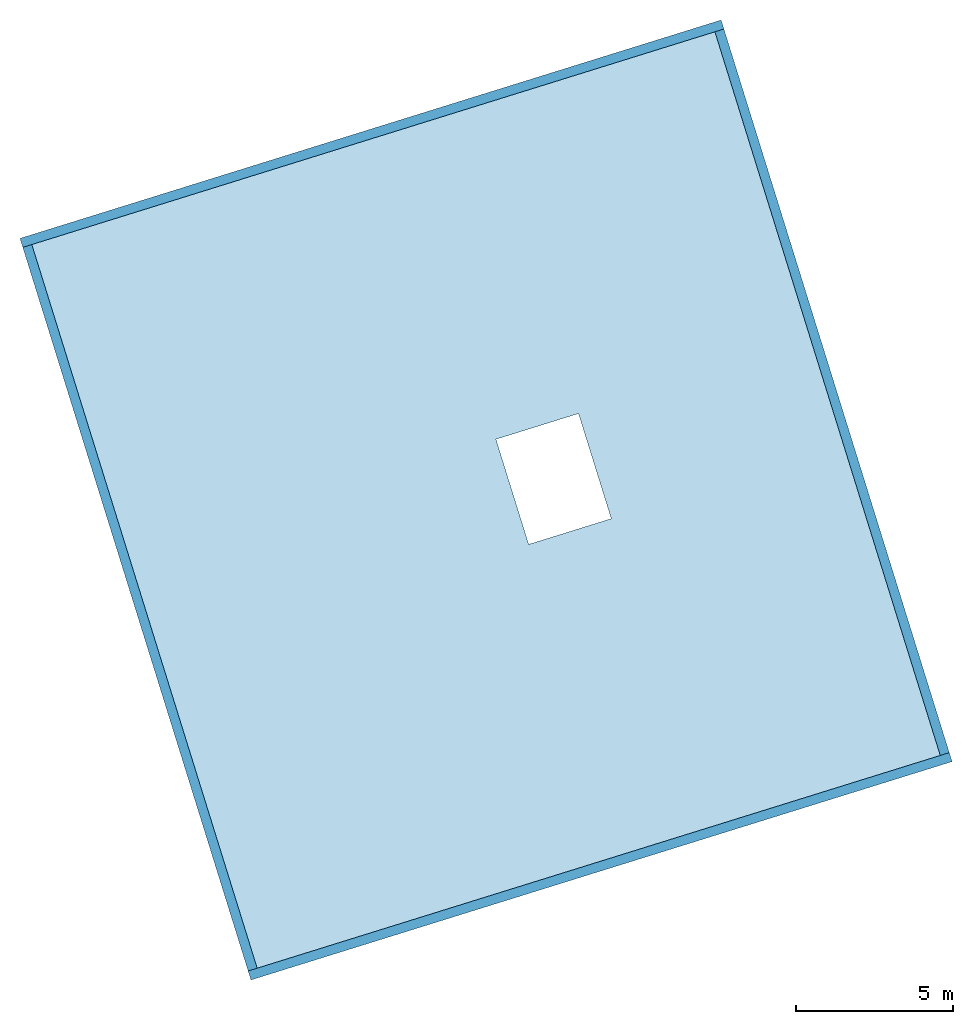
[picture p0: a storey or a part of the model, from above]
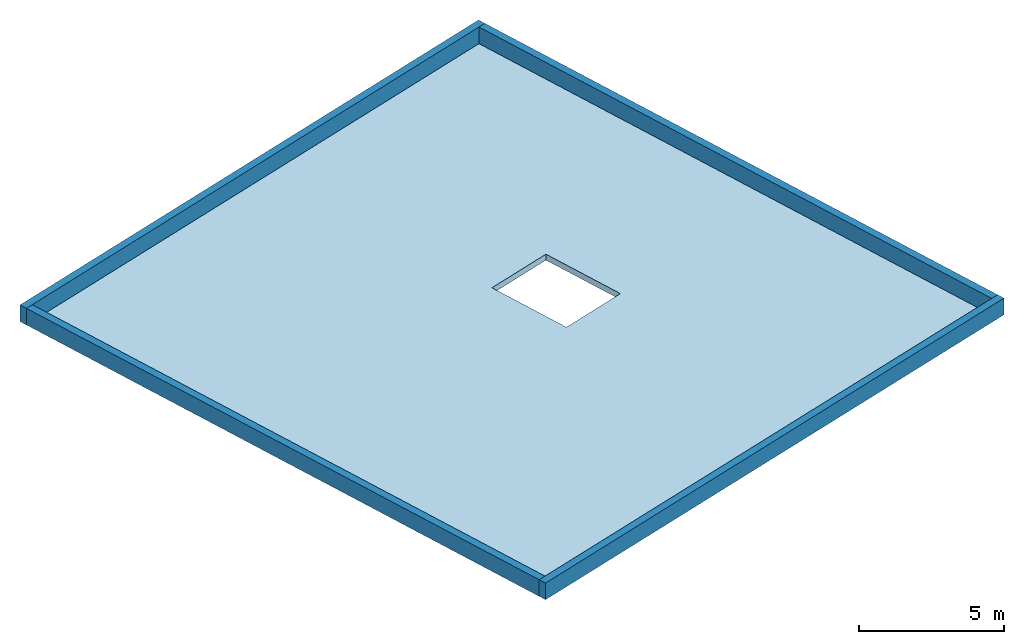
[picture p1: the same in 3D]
Properties of the parts of a building model (IFC4)

# File
Description: ViewDefinition [ReferenceView_V1.2], RevitIdentifiers [ContentGUID: 7b0fba1c-e461-43e6-a004-74300536da52, VersionGUID: d83a99a4-e321-4da3-b3c9-0b0068a0408a, NumberOfSaves: 137], Options [Excluded Entities: IfcGroup;], CoordinateReference [CoordinateBase: Survey Point, ProjectSite: Internal]
File name: MiniBIM 3.1 SO_02_VORM.ifc
Time: 2025-11-03T19:44:00+01:00
Organization: VORM Holding B.V.
Written by: IfcOpenShell 0.8.2
Made in: Bonsai 0.8.2

# IfcProject, 0000
LongName: Voorbeelmodel MiniBIM 3.1 SO-fase; Phase: PROJECTFASE

# IfcSite, Schiehaven
RefLatitude: 51, 54, 13, 78253; RefLongitude: 4, 27, 15, 99642; RefElevation: 3.5 m
Pset_SiteCommon - Reference: Project Information

# IfcBuilding, VORM huis
LongName: VORM huis
Pset_BuildingCommon - Reference: Project Information; NumberOfStoreys: 11; IsLandmarked: no
Pset_BuildingElementProxyCommon - Reference: Project Information; IsExternal: no
Pset_BuildingStoreyCommon - Reference: Project Information; AboveGround: no
Pset_BuildingSystemCommon - Reference: Project Information

# IfcBuildingStorey: Level:Level bouwniveau (PBP) (11)
In: VORM huis
Pset_BuildingStoreyCommon - Reference: Level bouwniveau (PBP)
Name | LongName | Elevation (m) | EntranceLevel | AboveGround
-1 kelder | -1 kelder | -3.2 | no | no
00 begane grond | begane grond | 0 | yes | yes
01 eerste verdieping | 01 eerste verdieping | 3.9 | no | yes
02 tweede verdieping | 02 tweede verdieping | 6.9 | no | yes
03 derde verdieping | 03 derde verdieping | 9.9 | no | yes
04 vierde verdieping | 04 vierde verdieping | 12.9 | no | yes
05 vijfde verdieping | 05 vijfde verdieping | 15.9 | no | yes
06 zesde verdieping | 06 zesde verdieping | 18.9 | no | yes
07 zevende verdieping | 07 zevende verdieping | 21.9 | no | yes
08 achtste verdieping | 08 achtste verdieping | 24.9 | no | yes
09 negende verdieping | 09 negende verdieping | 27.9 | no | yes

# IfcBuildingElementProxy: VORM_coordinatiepunt:CRS-coordinatiepunt, CRS-coordinatiepunt
In: 00 begane grond
Type - Classification: 00.00 (NL-SfB); Material: Blauw, Wit
Pset_BuildingElementProxyCommon - IsExternal: no; Reference: CRS-coordinatiepunt
Pset_EnvironmentalImpactIndicators - Reference: CRS-coordinatiepunt
Qto_BuildingElementProxyQuantities - NetSurfaceArea: 6.92096 m2; NetVolume: 0.458368 m3

# IfcBuildingElementProxy: VORM_coordinatiepunt:Lokaal-coordinatiepunt, Lokaal-coordinatiepunt
In: 00 begane grond
Type - Classification: 00.00 (NL-SfB); Material: Blauw, Wit
Pset_BuildingElementProxyCommon - Reference: Lokaal-coordinatiepunt; IsExternal: no
Pset_EnvironmentalImpactIndicators - Reference: Lokaal-coordinatiepunt
Qto_BuildingElementProxyQuantities - NetSurfaceArea: 7.78088 m2; NetVolume: 1.00022 m3

# IfcDoor: 31_DO_buitendeur dubbel:buitendeur zelfsluitend 30min (2)
In: 00 begane grond
Type - PredefinedType: DOOR; Classification: 31.30 buitenwandopeningen; gevuld met deuren, algemeen (verzamelniveau) (NL-SfB); Material: PD_a_buitenwandopeningen, metaal_aluminium_ntb
Type - Pset_DoorCommon - IsExternal: no; FireRating: 30
OverallHeight: 2.35 m; OverallWidth: 1.965 m
Pset_DoorCommon - Reference: buitendeur zelfsluitend 30min
Pset_EnvironmentalImpactIndicators - Reference: buitendeur zelfsluitend 30min
MiniBIM ILS - BouwwerkNummer: 02
Qto_DoorBaseQuantities - Width: 1.965 m; Height: 2.35 m; Perimeter: 1.965 m; Area: 4.61775 m2
Name | Gebruiksbestemming | Orientatie
Vluchtdeur | Woonfunctie | Oost
Vluchtdeur | Bijeenkomstfunctie | West

# IfcDoor: 31_DO_buitendeur enkel:buitendeur zelfsluitend 30min (2)
In: 00 begane grond
Type - PredefinedType: DOOR; Classification: 31.30 buitenwandopeningen; gevuld met deuren, algemeen (verzamelniveau) (NL-SfB); Material: PD_a_buitenwandopeningen, metaal_aluminium_ntb
Type - Pset_DoorCommon - IsExternal: no; FireRating: 30
OverallHeight: 2.35 m; OverallWidth: 1.05 m
Pset_DoorCommon - Reference: buitendeur zelfsluitend 30min
Pset_EnvironmentalImpactIndicators - Reference: buitendeur zelfsluitend 30min
MiniBIM ILS - BouwwerkNummer: 02; Gebruiksbestemming: Overige gebruiksfunctie
Qto_DoorBaseQuantities - Width: 1.05 m; Height: 2.35 m; Perimeter: 2 m; Area: 2.4675 m2
Name | Orientatie
Vluchtdeur | West
Vluchtdeur | Oost

# IfcDoor: 31_DO_buitendeur enkel:woningtoegangsdeur (3)
In: 00 begane grond
Type - PredefinedType: DOOR; OperationType: REVOLVING; Classification: 31.30 buitenwandopeningen; gevuld met deuren, algemeen (verzamelniveau) (NL-SfB); Material: PD_a_buitenwandopeningen, metaal_aluminium_ntb
Type - Woningtoegangsdeur:1 - PanelOperation: REVOLVING
Type - Pset_DoorCommon - IsExternal: no
OverallHeight: 2.35 m; OverallWidth: 1.05 m
Pset_DoorCommon - Reference: woningtoegangsdeur
Pset_EnvironmentalImpactIndicators - Reference: woningtoegangsdeur
MiniBIM ILS - BouwwerkNummer: 02; Gebruiksbestemming: Woonfunctie; Orientatie: Noord
Qto_DoorBaseQuantities - Width: 1.05 m; Height: 2.35 m; Perimeter: 2 m; Area: 2.4675 m2

# IfcDoor: 32_DO_binnendeur dubbel:binnendeur zelfsluitend 30min (6)
In: 00 begane grond
Type - PredefinedType: DOOR; Classification: 32.30 binnenwandopeningen; gevuld met deuren, algemeen (verzamelniveau) (NL-SfB); Material: PD_a_binnenwandopeningen, metaal_aluminium_ntb
Type - Pset_DoorCommon - IsExternal: no; FireRating: 30
OverallHeight: 2.35 m; OverallWidth: 1.95 m
Pset_DoorCommon - Reference: binnendeur zelfsluitend 30min
Pset_EnvironmentalImpactIndicators - Reference: binnendeur zelfsluitend 30min
Qto_DoorBaseQuantities - Width: 1.95 m; Height: 2.35 m; Perimeter: 1.95 m; Area: 4.5825 m2

# IfcDoor: 32_DO_binnendeur enkel:binnendeur zelfsluitend 30min (45)
Type - PredefinedType: DOOR; Classification: 32.30 binnenwandopeningen; gevuld met deuren, algemeen (verzamelniveau) (NL-SfB); Material: PD_a_binnenwandopeningen, metaal_aluminium_ntb
Type - Pset_DoorCommon - IsExternal: no; FireRating: 30
OverallHeight: 2.35 m; OverallWidth: 1.05 m
Pset_DoorCommon - Reference: binnendeur zelfsluitend 30min
Pset_EnvironmentalImpactIndicators - Reference: binnendeur zelfsluitend 30min
Qto_DoorBaseQuantities - Width: 1.05 m; Height: 2.35 m; Perimeter: 2 m; Area: 2.4675 m2
Name | In | BouwwerkNummer
4 x Vluchtdeur | 02 tweede verdieping | 01
4 x Vluchtdeur | 03 derde verdieping | 01
4 x Vluchtdeur | 04 vierde verdieping | 01
4 x Vluchtdeur | 05 vijfde verdieping | 01
4 x Vluchtdeur | 06 zesde verdieping | 01
4 x Vluchtdeur | 07 zevende verdieping | 01
4 x Vluchtdeur | 01 eerste verdieping | 01
4 x Vluchtdeur | 08 achtste verdieping | 01
2 x Vluchtdeur | -1 kelder | 01
6 x Vluchtdeur | -1 kelder
4 x Vluchtdeur | 00 begane grond | 01
Vluchtdeur | 00 begane grond

# IfcDoor: 32_DO_binnendeur enkel:woningtoegangsdeur (46)
Type - PredefinedType: DOOR; OperationType: REVOLVING; Classification: 32.30 binnenwandopeningen; gevuld met deuren, algemeen (verzamelniveau) (NL-SfB); Material: PD_a_binnenwandopeningen, metaal_aluminium_ntb
Type - Woningtoegangsdeur:1 - PanelOperation: REVOLVING
Type - Pset_DoorCommon - IsExternal: no
OverallHeight: 2.35 m; OverallWidth: 1.05 m
Pset_DoorCommon - Reference: woningtoegangsdeur
Pset_EnvironmentalImpactIndicators - Reference: woningtoegangsdeur
MiniBIM ILS - BouwwerkNummer: 02
Qto_DoorBaseQuantities - Width: 1.05 m; Height: 2.35 m; Perimeter: 2 m; Area: 2.4675 m2
Name | In
6 x Woningtoegangsdeur | 02 tweede verdieping
6 x Woningtoegangsdeur | 03 derde verdieping
6 x Woningtoegangsdeur | 04 vierde verdieping
6 x Woningtoegangsdeur | 05 vijfde verdieping
6 x Woningtoegangsdeur | 06 zesde verdieping
6 x Woningtoegangsdeur | 07 zevende verdieping
6 x Woningtoegangsdeur | 08 achtste verdieping
4 x Woningtoegangsdeur | 01 eerste verdieping

# IfcDoor: 66_WI_liftdeur:brandweerlift - eenzijdig toegankelijk (2)
In: -1 kelder
Type - PredefinedType: DOOR; Classification: 66.10 transport; liftinstallaties, algemeen (verzamelniveau) (NL-SfB); Material: metaal_aluminium_ntb
OverallHeight: 2.4 m; OverallWidth: 1 m
Pset_DoorCommon - IsExternal: no; Reference: brandweerlift - eenzijdig toegankelijk
Pset_EnvironmentalImpactIndicators - Reference: brandweerlift - eenzijdig toegankelijk
MiniBIM ILS - BouwwerkNummer: 01
Qto_DoorBaseQuantities - Width: 1 m; Height: 2.4 m; Perimeter: 1.1 m; Area: 2.4 m2

# IfcDoor: 66_WI_liftdeur:brandweerlift - tweezijdig toegankelijk (18)
Type - PredefinedType: DOOR; Classification: 66.10 transport; liftinstallaties, algemeen (verzamelniveau) (NL-SfB); Material: metaal_aluminium_ntb
OverallHeight: 2.4 m; OverallWidth: 1 m
Pset_DoorCommon - IsExternal: no; Reference: brandweerlift - tweezijdig toegankelijk
Pset_EnvironmentalImpactIndicators - Reference: brandweerlift - tweezijdig toegankelijk
MiniBIM ILS - BouwwerkNummer: 01
Qto_DoorBaseQuantities - Width: 1 m; Height: 2.4 m; Perimeter: 1.1 m; Area: 2.4 m2
Name | In
2 x Brandweerlift | 02 tweede verdieping
2 x Brandweerlift | 03 derde verdieping
2 x Brandweerlift | 04 vierde verdieping
2 x Brandweerlift | 05 vijfde verdieping
2 x Brandweerlift | 06 zesde verdieping
2 x Brandweerlift | 07 zevende verdieping
2 x Brandweerlift | 01 eerste verdieping
2 x Brandweerlift | 08 achtste verdieping
2 x Brandweerlift | 00 begane grond

# IfcOpeningElement (229)
PredefinedType: OPENING
Name | In | Depth (m) | Height (m) | Width (m)
8 x Constructieve wand | 02 tweede verdieping | 0.25 | 2.4 | 1.2 | Pset_EnvironmentalImpactIndicators - Reference: 28_WA_skelet_wand 250mm_gen; sets with these values: 2
Constructieve vloer | 02 tweede verdieping |  | 2.75 | 3.5 | Pset_EnvironmentalImpactIndicators - Reference: 28_FL_skelet_vloer 250mm; sets with these values: 2
Constructieve vloer | 02 tweede verdieping |  | 1.2 | 3.3 | Pset_EnvironmentalImpactIndicators - Reference: 28_FL_skelet_vloer 250mm; sets with these values: 2
8 x Constructieve wand | 03 derde verdieping | 0.25 | 2.4 | 1.2 | Pset_EnvironmentalImpactIndicators - Reference: 28_WA_skelet_wand 250mm_gen; sets with these values: 2
Constructieve vloer | 03 derde verdieping |  | 2.75 | 3.5 | Pset_EnvironmentalImpactIndicators - Reference: 28_FL_skelet_vloer 250mm; sets with these values: 2
Constructieve vloer | 03 derde verdieping |  | 1.2 | 3.3 | Pset_EnvironmentalImpactIndicators - Reference: 28_FL_skelet_vloer 250mm; sets with these values: 2
8 x Constructieve wand | 04 vierde verdieping | 0.25 | 2.4 | 1.2 | Pset_EnvironmentalImpactIndicators - Reference: 28_WA_skelet_wand 250mm_gen; sets with these values: 2
Constructieve vloer | 04 vierde verdieping |  | 2.75 | 3.5 | Pset_EnvironmentalImpactIndicators - Reference: 28_FL_skelet_vloer 250mm; sets with these values: 2
Constructieve vloer | 04 vierde verdieping |  | 1.2 | 3.3 | Pset_EnvironmentalImpactIndicators - Reference: 28_FL_skelet_vloer 250mm; sets with these values: 2
8 x Constructieve wand | 05 vijfde verdieping | 0.25 | 2.4 | 1.2 | Pset_EnvironmentalImpactIndicators - Reference: 28_WA_skelet_wand 250mm_gen; sets with these values: 2
Constructieve vloer | 05 vijfde verdieping |  | 2.75 | 3.5 | Pset_EnvironmentalImpactIndicators - Reference: 28_FL_skelet_vloer 250mm; sets with these values: 2
Constructieve vloer | 05 vijfde verdieping |  | 1.2 | 3.3 | Pset_EnvironmentalImpactIndicators - Reference: 28_FL_skelet_vloer 250mm; sets with these values: 2
8 x Constructieve wand | 06 zesde verdieping | 0.25 | 2.4 | 1.2 | Pset_EnvironmentalImpactIndicators - Reference: 28_WA_skelet_wand 250mm_gen; sets with these values: 2
Constructieve vloer | 06 zesde verdieping |  | 2.75 | 3.5 | Pset_EnvironmentalImpactIndicators - Reference: 28_FL_skelet_vloer 250mm; sets with these values: 2
Constructieve vloer | 06 zesde verdieping |  | 1.2 | 3.3 | Pset_EnvironmentalImpactIndicators - Reference: 28_FL_skelet_vloer 250mm; sets with these values: 2
8 x Constructieve wand | 07 zevende verdieping | 0.25 | 2.4 | 1.2 | Pset_EnvironmentalImpactIndicators - Reference: 28_WA_skelet_wand 250mm_gen; sets with these values: 2
Constructieve vloer | 07 zevende verdieping |  | 2.75 | 3.5 | Pset_EnvironmentalImpactIndicators - Reference: 28_FL_skelet_vloer 250mm; sets with these values: 2
Constructieve vloer | 07 zevende verdieping |  | 1.2 | 3.3 | Pset_EnvironmentalImpactIndicators - Reference: 28_FL_skelet_vloer 250mm; sets with these values: 2
8 x Constructieve wand | 01 eerste verdieping | 0.25 | 2.4 | 1.2 | Pset_EnvironmentalImpactIndicators - Reference: 28_WA_skelet_wand 250mm_gen; sets with these values: 2
2 x Constructieve wand | 01 eerste verdieping | 0.25 | 2.4 | 2 | Pset_EnvironmentalImpactIndicators - Reference: 28_WA_skelet_wand 250mm_gen; sets with these values: 2
Constructieve vloer | 01 eerste verdieping |  | 2.75 | 3.5 | Pset_EnvironmentalImpactIndicators - Reference: 28_FL_skelet_vloer 250mm; sets with these values: 2
Constructieve vloer | 01 eerste verdieping |  | 1.2 | 3.3 | Pset_EnvironmentalImpactIndicators - Reference: 28_FL_skelet_vloer 250mm; sets with these values: 2
8 x Constructieve wand | 08 achtste verdieping | 0.25 | 2.4 | 1.2 | Pset_EnvironmentalImpactIndicators - Reference: 28_WA_skelet_wand 250mm_gen; sets with these values: 2
Constructieve vloer | 08 achtste verdieping |  | 2.75 | 3.5 | Pset_EnvironmentalImpactIndicators - Reference: 28_FL_skelet_vloer 250mm; sets with these values: 2
Constructieve vloer | 08 achtste verdieping |  | 1.2 | 3.3 | Pset_EnvironmentalImpactIndicators - Reference: 28_FL_skelet_vloer 250mm; sets with these values: 2
Dakvloer | 09 negende verdieping |  | 2.75 | 3.5 | Pset_EnvironmentalImpactIndicators - Reference: 28_FL_skelet_dakvloer 250mm; sets with these values: 2
Vluchtdeur | -1 kelder | 1.05 | 2.35 | 0.1 | Pset_EnvironmentalImpactIndicators - Reference: binnendeur zelfsluitend 30min; sets with these values: 2; Classification: 32.30 binnenwandopeningen; gevuld met deuren, algemeen (verzamelniveau) (NL-SfB)
3 x Vluchtdeur | 00 begane grond | 3.048 | 2.35 | 1.05 | Pset_EnvironmentalImpactIndicators - Reference: buitendeur zelfsluitend 30min; sets with these values: 2; Classification: 31.30 buitenwandopeningen; gevuld met deuren, algemeen (verzamelniveau) (NL-SfB)
2 x Vluchtdeur | 00 begane grond | 3.048 | 2.35 | 1.965 | Pset_EnvironmentalImpactIndicators - Reference: buitendeur zelfsluitend 30min; sets with these values: 2; Classification: 31.30 buitenwandopeningen; gevuld met deuren, algemeen (verzamelniveau) (NL-SfB)
Constructieve vloer | 00 begane grond |  | 2.75 | 3.5 | Pset_EnvironmentalImpactIndicators - Reference: 28_FL_skelet_vloer 250mm; sets with these values: 2
Constructieve vloer | 00 begane grond |  | 1.2 | 3.3 | Pset_EnvironmentalImpactIndicators - Reference: 28_FL_skelet_vloer 250mm; sets with these values: 2
3 x Woningtoegangsdeur | 00 begane grond | 3.048 | 2.35 | 1.05 | Pset_EnvironmentalImpactIndicators - Reference: woningtoegangsdeur; sets with these values: 2; Classification: 31.30 buitenwandopeningen; gevuld met deuren, algemeen (verzamelniveau) (NL-SfB)
2 x Constructieve wand | 00 begane grond | 0.25 | 2.4 | 2.1 | Pset_EnvironmentalImpactIndicators - Reference: 28_WA_skelet_wand 250mm_gen; sets with these values: 2
2 x Constructieve wand | 00 begane grond | 0.25 | 2.4 | 2 | Pset_EnvironmentalImpactIndicators - Reference: 28_WA_skelet_wand 250mm_gen; sets with these values: 2
Funderingvloer | -1 kelder |  | 2.75 | 3.5 | Pset_EnvironmentalImpactIndicators - Reference: 13_FL_funderingvloer 250mm; sets with these values: 2
2 x Woningtoegangsdeur | 02 tweede verdieping | 0.25 | 2.35 | 1.05
2 x Brandweerlift | 02 tweede verdieping | 0.75631 | 2.4 | 1
4 x Woningtoegangsdeur | 02 tweede verdieping | 0.25 | 1.05 | 2.35
2 x Vluchtdeur | 02 tweede verdieping | 0.1 | 1.05 | 2.35
2 x Vluchtdeur | 02 tweede verdieping | 0.1 | 2.35 | 1.05
2 x Woningtoegangsdeur | 03 derde verdieping | 0.25 | 2.35 | 1.05
2 x Brandweerlift | 03 derde verdieping | 0.75631 | 2.4 | 1
4 x Woningtoegangsdeur | 03 derde verdieping | 0.25 | 1.05 | 2.35
2 x Vluchtdeur | 03 derde verdieping | 0.1 | 1.05 | 2.35
2 x Vluchtdeur | 03 derde verdieping | 0.1 | 2.35 | 1.05
2 x Woningtoegangsdeur | 04 vierde verdieping | 0.25 | 2.35 | 1.05
2 x Brandweerlift | 04 vierde verdieping | 0.75631 | 2.4 | 1
4 x Woningtoegangsdeur | 04 vierde verdieping | 0.25 | 1.05 | 2.35
2 x Vluchtdeur | 04 vierde verdieping | 0.1 | 1.05 | 2.35
2 x Vluchtdeur | 04 vierde verdieping | 0.1 | 2.35 | 1.05
2 x Woningtoegangsdeur | 05 vijfde verdieping | 0.25 | 2.35 | 1.05
2 x Brandweerlift | 05 vijfde verdieping | 0.75631 | 2.4 | 1
4 x Woningtoegangsdeur | 05 vijfde verdieping | 0.25 | 1.05 | 2.35
2 x Vluchtdeur | 05 vijfde verdieping | 0.1 | 1.05 | 2.35
2 x Vluchtdeur | 05 vijfde verdieping | 0.1 | 2.35 | 1.05
2 x Woningtoegangsdeur | 06 zesde verdieping | 0.25 | 2.35 | 1.05
2 x Brandweerlift | 06 zesde verdieping | 0.75631 | 2.4 | 1
4 x Woningtoegangsdeur | 06 zesde verdieping | 0.25 | 1.05 | 2.35
2 x Vluchtdeur | 06 zesde verdieping | 0.1 | 1.05 | 2.35
2 x Vluchtdeur | 06 zesde verdieping | 0.1 | 2.35 | 1.05
2 x Woningtoegangsdeur | 07 zevende verdieping | 0.25 | 2.35 | 1.05
2 x Brandweerlift | 07 zevende verdieping | 0.75631 | 2.4 | 1
4 x Woningtoegangsdeur | 07 zevende verdieping | 0.25 | 1.05 | 2.35
2 x Vluchtdeur | 07 zevende verdieping | 0.1 | 1.05 | 2.35
2 x Vluchtdeur | 07 zevende verdieping | 0.1 | 2.35 | 1.05
2 x Brandweerlift | 01 eerste verdieping | 0.75631 | 2.4 | 1
4 x Woningtoegangsdeur | 01 eerste verdieping | 0.25 | 1.05 | 2.35
2 x Vluchtdeur | 01 eerste verdieping | 0.1 | 1.05 | 2.35
2 x Vluchtdeur | 01 eerste verdieping | 0.1 | 2.35 | 1.05
2 x Woningtoegangsdeur | 08 achtste verdieping | 0.25 | 2.35 | 1.05
2 x Brandweerlift | 08 achtste verdieping | 0.75631 | 2.4 | 1
4 x Woningtoegangsdeur | 08 achtste verdieping | 0.25 | 1.05 | 2.35
2 x Vluchtdeur | 08 achtste verdieping | 0.1 | 1.05 | 2.35
2 x Vluchtdeur | 08 achtste verdieping | 0.1 | 2.35 | 1.05
2 x Brandweerlift | -1 kelder | 0.75631 | 2.4 | 1
2 x Vluchtdeur | -1 kelder | 0.2 | 1.05 | 2.35
4 x Vluchtdeur | -1 kelder | 0.1 | 1.05 | 2.35
2 x Vluchtdeur | -1 kelder | 0.25 | 2.35 | 1.05
Vluchtdeur | 00 begane grond | 0.25 | 1.05 | 2.35
3 x Woningtoegangsdeur | 00 begane grond | 0.3 | 2.35 | 1.05
4 x Vluchtdeur | 00 begane grond | 0.1 | 2.35 | 1.05
4 x Vluchtdeur | 00 begane grond | 3.048 | 2.35 | 1.05
Vluchtdeur | 00 begane grond | 0.25 | 2.35 | 1.05
4 x Vluchtdeur | 00 begane grond | 0.25 | 1.95 | 2.35
Vluchtdeur | 00 begane grond | 0.25 | 2.35 | 1.95
2 x Brandweerlift | 00 begane grond | 0.75631 | 2.4 | 1
Vluchtdeur | 00 begane grond | 0.1 | 2.35 | 1.95
2 x Vluchtdeur | 00 begane grond | 0.3 | 1.965 | 2.35
2 x Vluchtdeur | 00 begane grond | 3.048 | 2.35 | 1.965
Vluchtdeur | 00 begane grond | 0.3 | 1.05 | 2.35

# IfcSlab: Floor:13_FL_funderingvloer 250mm, Funderingvloer
In: -1 kelder
Type - PredefinedType: FLOOR; Material: beton_gewapend_ihw
Type - Pset_ReinforcementBarPitchOfSlab - Description: Funderingvloer
Type - Pset_SlabCommon - LoadBearing: yes
Classification: 13.20 vloeren op grondslag; constructief, algemeen (verzamelniveau) (NL-SfB)
Pset_EnvironmentalImpactIndicators - Reference: 13_FL_funderingvloer 250mm; sets with these values: 2
Pset_SlabCommon - IsExternal: no; LoadBearing: no; PitchAngle: 0 deg; Reference: 13_FL_funderingvloer 250mm
Qto_SlabBaseQuantities - Width: 10.3 m; Length: 7.5 m; Depth: 0.25 m; Perimeter: 116.798 m; GrossArea: 77.25 m2; NetArea: 67.625 m2; GrossVolume: 19.3125 m3; NetVolume: 16.9063 m3

# IfcSlab: Floor:23_FL_skelet_balkon 200mm (42)
Type - PredefinedType: FLOOR; Material: beton_gewapend_prefab-element
Type - Pset_ReinforcementBarPitchOfSlab - Description: Balkonvloer
Type - Pset_SlabCommon - LoadBearing: no
Classification: 23.10 vloeren; niet constructief, algemeen (verzamelniveau) (NL-SfB)
Pset_EnvironmentalImpactIndicators - Reference: 23_FL_skelet_balkon 200mm; sets with these values: 2
Pset_SlabCommon - PitchAngle: 0 deg; IsExternal: yes; Reference: 23_FL_skelet_balkon 200mm
Qto_SlabBaseQuantities - Width: 2.2 m; Length: 3 m; Depth: 0.2 m; Perimeter: 34.1207 m; GrossArea: 6.6 m2; NetArea: 6.6 m2; GrossVolume: 1.32 m3; NetVolume: 1.32 m3
Name | In
6 x Balkonvloer | 03 derde verdieping
6 x Balkonvloer | 04 vierde verdieping
6 x Balkonvloer | 05 vijfde verdieping
6 x Balkonvloer | 06 zesde verdieping
6 x Balkonvloer | 07 zevende verdieping
6 x Balkonvloer | 08 achtste verdieping
6 x Balkonvloer | 02 tweede verdieping

# IfcSlab: Floor:28_FL_skelet_dakterrasvloer 250mm (6)
Type - PredefinedType: ROOF; Material: beton_gewapend_ihw
Type - Pset_ReinforcementBarPitchOfSlab - Description: Begaanbare dakvloer
Type - Pset_SlabCommon - LoadBearing: yes
Classification: 27.10 daken; niet constructief, algemeen (verzamelniveau) (NL-SfB)
Pset_EnvironmentalImpactIndicators - Reference: 28_FL_skelet_dakterrasvloer 250mm; sets with these values: 2
Pset_SlabCommon - IsExternal: no; LoadBearing: no; PitchAngle: 0 deg; Reference: 28_FL_skelet_dakterrasvloer 250mm
Qto_SlabBaseQuantities - Depth: 0.25 m
Name | In | Width (m) | Length (m) | Perimeter (m) | GrossArea (m2) = NetArea (m2) | GrossVolume (m3) = NetVolume (m3)
4 x Begaanbare dakvloer | 01 eerste verdieping | 2 | 2.4 | 28.8714 | 4.8 | 1.2
2 x Begaanbare dakvloer | 02 tweede verdieping | 22.75 | 4.625 | 179.626 | 105.219 | 26.3047

# IfcSlab: Floor:28_FL_skelet_dakvloer 250mm, Dakvloer
In: 09 negende verdieping
Type - PredefinedType: ROOF; Material: beton_gewapend_ihw
Type - Pset_ReinforcementBarPitchOfSlab - Description: Dakvloer
Type - Pset_SlabCommon - LoadBearing: yes
Classification: 27.10 daken; niet constructief, algemeen (verzamelniveau) (NL-SfB)
Pset_EnvironmentalImpactIndicators - Reference: 28_FL_skelet_dakvloer 250mm; sets with these values: 2
Pset_SlabCommon - IsExternal: no; LoadBearing: no; PitchAngle: 0 deg; Reference: 28_FL_skelet_dakvloer 250mm
Qto_SlabBaseQuantities - Width: 22.75 m; Length: 24.1 m; Depth: 0.25 m; Perimeter: 307.415 m; GrossArea: 548.275 m2; NetArea: 538.65 m2; GrossVolume: 137.069 m3; NetVolume: 134.662 m3

# IfcSlab: Floor:28_FL_skelet_vloer 250mm (9)
Type - PredefinedType: FLOOR; Material: beton_gewapend_ihw
Type - Pset_ReinforcementBarPitchOfSlab - Description: Constructieve vloer
Type - Pset_SlabCommon - LoadBearing: yes
Classification: 28.20 hoofddraagconstructies; wanden en vloeren, algemeen (verzamelniveau) (NL-SfB)
Pset_EnvironmentalImpactIndicators - Reference: 28_FL_skelet_vloer 250mm; sets with these values: 2
Pset_SlabCommon - IsExternal: no; LoadBearing: no; Reference: 28_FL_skelet_vloer 250mm; PitchAngle: 0 deg
Qto_SlabBaseQuantities - Depth: 0.25 m
Name | In | Width (m) | Length (m) | Perimeter (m) | GrossArea (m2) | NetArea (m2) | GrossVolume (m3) | NetVolume (m3)
Constructieve vloer | 02 tweede verdieping | 22.75 | 24.1 | 307.415 | 548.275 | 530.73 | 137.069 | 132.682
Constructieve vloer | 03 derde verdieping | 22.75 | 24.1 | 307.415 | 548.275 | 530.73 | 137.069 | 132.682
Constructieve vloer | 04 vierde verdieping | 22.75 | 24.1 | 307.415 | 548.275 | 530.73 | 137.069 | 132.682
Constructieve vloer | 05 vijfde verdieping | 22.75 | 24.1 | 307.415 | 548.275 | 530.73 | 137.069 | 132.682
Constructieve vloer | 06 zesde verdieping | 22.75 | 24.1 | 307.415 | 548.275 | 530.73 | 137.069 | 132.682
Constructieve vloer | 07 zevende verdieping | 22.75 | 24.1 | 307.415 | 548.275 | 530.73 | 137.069 | 132.682
Constructieve vloer | 01 eerste verdieping |  |  | 419.291 | 737.652 | 720.107 | 184.413 | 180.027
Constructieve vloer | 08 achtste verdieping | 22.75 | 24.1 | 307.415 | 548.275 | 530.73 | 137.069 | 132.682
Constructieve vloer | 00 begane grond | 22.75 | 33.35 | 368.11 | 758.712 | 741.167 | 189.678 | 185.292

# IfcStair: Trap (18)
Type - PredefinedType: STRAIGHT_RUN_STAIR
Type - Pset_StairCommon - IsExternal: no; NosingLength: 0 m; NumberOfRiser: 0; NumberOfTreads: 0
Type - Pset_StairFlightCommon - NosingLength: 0 m; NumberOfRiser: 0; NumberOfTreads: 0
Classification: 24.10 trappen en hellingen; trappen, algemeen (verzamelniveau) (NL-SfB)
Pset_EnvironmentalImpactIndicators - Reference: NLRS_24_STR_reguliere trap-woonfunctie-breedte 1200mm_gen
Pset_StairCommon - Reference: NLRS_24_STR_reguliere trap-woonfunctie-breedte 1200mm_gen; TreadLength: 0.22 m; WalkingLineOffset: 1.9685 m; TreadLengthAtOffset: 0.22 m; TreadLengthAtInnerSide: 0.22 m
Pset_StairFlightCommon - Reference: NLRS_24_STR_reguliere trap-woonfunctie-breedte 1200mm_gen; TreadLength: 0.22 m; WalkingLineOffset: 1.9685 m; TreadLengthAtOffset: 0.22 m; TreadLengthAtInnerSide: 0.22 m
Name | In | Pset_StairCommon, NumberOfRiser = Pset_StairCommon, NumberOfTreads = Pset_StairFlightCommon, NumberOfRiser = Pset_StairFlightCommon, NumberOfTreads | Pset_StairCommon, RiserHeight (m) = Pset_StairFlightCommon, RiserHeight (m)
2 x Hoofdtrap | 02 tweede verdieping | 16 | 0.1875
2 x Hoofdtrap | 03 derde verdieping | 16 | 0.1875
2 x Hoofdtrap | 04 vierde verdieping | 16 | 0.1875
2 x Hoofdtrap | 05 vijfde verdieping | 16 | 0.1875
2 x Hoofdtrap | 06 zesde verdieping | 16 | 0.1875
2 x Hoofdtrap | 07 zevende verdieping | 16 | 0.1875
2 x Hoofdtrap | 01 eerste verdieping | 16 | 0.1875
2 x Hoofdtrap | -1 kelder | 16 | 0.188235
2 x Hoofdtrap | 00 begane grond | 21 | 0.185714

# IfcStairFlight: Monolithic Run:NLRS_24_STRR_trap-beton prefab-monolithisch-recht_gen_rsf (18)
Type - PredefinedType: STRAIGHT
Type - Pset_StairFlightCommon - NosingLength: 0 m
Classification: 24.10 trappen en hellingen; trappen, algemeen (verzamelniveau) (NL-SfB); Material: beton_gewapend_prefab-element
Pset_EnvironmentalImpactIndicators - Reference: NLRS_24_STRR_trap-beton prefab-monolithisch-recht_gen_rsf
Pset_StairFlightCommon - Reference: NLRS_24_STRR_trap-beton prefab-monolithisch-recht_gen_rsf; TreadLength: 0.22 m; WalkingLineOffset: 1.9685 m; TreadLengthAtOffset: 0.22 m; TreadLengthAtInnerSide: 0.22 m
Name | In | NumberOfRiser = NumberOfTreads | RiserHeight (m) | Length (m) | NetVolume (m3)
2 x Hoofdtrap Run 1 | 02 tweede verdieping | 16 | 0.1875 | 3.52 | 1.20115
2 x Hoofdtrap Run 1 | 03 derde verdieping | 16 | 0.1875 | 3.52 | 1.20115
2 x Hoofdtrap Run 1 | 04 vierde verdieping | 16 | 0.1875 | 3.52 | 1.20115
2 x Hoofdtrap Run 1 | 05 vijfde verdieping | 16 | 0.1875 | 3.52 | 1.20115
2 x Hoofdtrap Run 1 | 06 zesde verdieping | 16 | 0.1875 | 3.52 | 1.20115
2 x Hoofdtrap Run 1 | 07 zevende verdieping | 16 | 0.1875 | 3.52 | 1.20115
2 x Hoofdtrap Run 1 | 01 eerste verdieping | 16 | 0.1875 | 3.52 | 1.20115
2 x Hoofdtrap Run 1 | -1 kelder | 16 | 0.188235 | 3.52 | 1.20409
2 x Hoofdtrap Run 1 | 00 begane grond | 21 | 0.185714 | 4.62 | 1.5757

# IfcWall: Basic Wall:21_WA_gevel_binnenspouwwand 100mm_gen (54)
Type - PredefinedType: STANDARD
Type - Pset_ReinforcementBarPitchOfWall - Description: Binnenspouwblad
Type - Pset_WallCommon - LoadBearing: no
Classification: 21.12 buitenwanden; niet constructief, spouwwanden (NL-SfB); Material: ntb_ntb_ntb
Qto_WallBaseQuantities - Length: 7.25 m; Width: 0.1 m; GrossFootprintArea: 0.725 m2
Pset_EnvironmentalImpactIndicators - Reference: 21_WA_gevel_binnenspouwwand 100mm_gen; sets with these values: 2
Pset_WallCommon - ExtendToStructure: no; Reference: 21_WA_gevel_binnenspouwwand 100mm_gen; IsExternal: yes
Name | In | Height (m) | GrossVolume (m3) = NetVolume (m3) | GrossSideArea (m2) = NetSideArea (m2)
6 x Binnenspouwblad | 02 tweede verdieping | 2.75 | 1.99375 | 19.9375
6 x Binnenspouwblad | 03 derde verdieping | 2.75 | 1.99375 | 19.9375
6 x Binnenspouwblad | 04 vierde verdieping | 2.75 | 1.99375 | 19.9375
6 x Binnenspouwblad | 05 vijfde verdieping | 2.75 | 1.99375 | 19.9375
6 x Binnenspouwblad | 06 zesde verdieping | 2.75 | 1.99375 | 19.9375
6 x Binnenspouwblad | 07 zevende verdieping | 2.75 | 1.99375 | 19.9375
6 x Binnenspouwblad | 01 eerste verdieping | 2.75 | 1.99375 | 19.9375
6 x Binnenspouwblad | 08 achtste verdieping | 2.75 | 1.99375 | 19.9375
3 x Binnenspouwblad | 00 begane grond | 3.65 | 2.64625 | 26.4625
3 x Binnenspouwblad | 00 begane grond | 3.65 | 2.3995 | 23.995

# IfcWall: Basic Wall:21_WA_gevel_buitenwand 100mm_gen (4)
In: 01 eerste verdieping
Type - PredefinedType: STANDARD
Type - Pset_ReinforcementBarPitchOfWall - Description: Gevelwand
Type - Pset_WallCommon - LoadBearing: no
Classification: 21.10 buitenwanden; niet constructief, algemeen (verzamelniveau) (NL-SfB); Material: ntb_ntb_ntb
Qto_WallBaseQuantities - Height: 3 m; Length: 2.4 m; Width: 0.1 m; GrossFootprintArea: 0.24 m2; GrossVolume: 0.72 m3; GrossSideArea: 7.2 m2; NetSideArea: 7.2 m2; NetVolume: 0.72 m3
Pset_EnvironmentalImpactIndicators - Reference: 21_WA_gevel_buitenwand 100mm_gen; sets with these values: 2
Pset_WallCommon - ExtendToStructure: no; IsExternal: yes; Reference: 21_WA_gevel_buitenwand 100mm_gen
MiniBIM ILS - BouwwerkNummer: 02; Gebruiksbestemming: Woonfunctie; Glaspercentage: 40
Name | Orientatie
2 x Gevelwand | Oost
2 x Gevelwand | West

# IfcWall: Basic Wall:21_WA_gevel_buitenwand 150mm_gen (12)
In: 01 eerste verdieping
Type - PredefinedType: STANDARD
Type - Pset_ReinforcementBarPitchOfWall - Description: Gevelwand
Type - Pset_WallCommon - LoadBearing: no
Classification: 21.10 buitenwanden; niet constructief, algemeen (verzamelniveau) (NL-SfB); Material: ntb_ntb_ntb
Qto_WallBaseQuantities - Height: 2.75 m; Width: 0.15 m
Pset_EnvironmentalImpactIndicators - Reference: 21_WA_gevel_buitenwand 150mm_gen; sets with these values: 2
Pset_WallCommon - ExtendToStructure: no; IsExternal: yes; Reference: 21_WA_gevel_buitenwand 150mm_gen
MiniBIM ILS - BouwwerkNummer: 02; Gebruiksbestemming: Woonfunctie; Glaspercentage: 40
Name | Length (m) | GrossFootprintArea (m2) | GrossVolume (m3) | GrossSideArea (m2) = NetSideArea (m2) | NetVolume (m3) | Orientatie
2 x Gevelwand | 1.95 | 0.2925 | 0.804375 | 5.3625 | 0.804375 | Noord
2 x Gevelwand | 2.55 | 0.3825 | 1.05187 | 7.0125 | 1.05187 | Oost
2 x Gevelwand | 1.8 | 0.27 | 0.7425 | 4.95 | 0.7425 | Zuid
2 x Gevelwand | 1.95 | 0.2925 | 0.804375 | 5.3625 | 0.804375 | Zuid
2 x Gevelwand | 1.8 | 0.27 | 0.7425 | 4.95 | 0.7425 | Noord
2 x Gevelwand | 2.55 | 0.3825 | 1.05187 | 7.0125 | 1.05188 | West

# IfcWall: Basic Wall:21_WA_gevel_buitenwand 300mm_gen (56)
Type - PredefinedType: STANDARD
Type - Pset_ReinforcementBarPitchOfWall - Description: Gevelwand
Type - Pset_WallCommon - LoadBearing: no
Classification: 21.10 buitenwanden; niet constructief, algemeen (verzamelniveau) (NL-SfB); Material: ntb_ntb_ntb
Qto_WallBaseQuantities - Width: 0.3 m
Pset_EnvironmentalImpactIndicators - Reference: 21_WA_gevel_buitenwand 300mm_gen; sets with these values: 2
Pset_WallCommon - ExtendToStructure: no; IsExternal: yes; Reference: 21_WA_gevel_buitenwand 300mm_gen
Name | In | Height (m) | Length (m) | GrossFootprintArea (m2) | GrossVolume (m3) | GrossSideArea (m2) | NetSideArea (m2) | NetVolume (m3) | BouwwerkNummer | Gebruiksbestemming | Glaspercentage | Orientatie
Gevelwand | 02 tweede verdieping | 3 | 24.1 | 7.23 | 21.69 | 72.3 | 72.3 | 21.69 | 01 | Woonfunctie | 40 | Oost
Gevelwand | 02 tweede verdieping | 3 | 23.35 | 7.005 | 21.015 | 70.05 | 70.05 | 21.015 | 02 | Woonfunctie | 40 | Zuid
Gevelwand | 02 tweede verdieping | 3 | 24.1 | 7.23 | 21.69 | 72.3 | 72.3 | 21.69 | 02 | Woonfunctie | 40 | West
Gevelwand | 02 tweede verdieping | 3 | 23.35 | 7.005 | 21.015 | 70.05 | 70.05 | 21.015 | 01 | Woonfunctie | 40 | Noord
Gevelwand | 03 derde verdieping | 3 | 24.1 | 7.23 | 21.69 | 72.3 | 72.3 | 21.69 | 01 | Woonfunctie | 40 | Oost
Gevelwand | 03 derde verdieping | 3 | 23.35 | 7.005 | 21.015 | 70.05 | 70.05 | 21.015 | 02 | Woonfunctie | 40 | Zuid
Gevelwand | 03 derde verdieping | 3 | 24.1 | 7.23 | 21.69 | 72.3 | 72.3 | 21.69 | 02 | Woonfunctie | 40 | West
Gevelwand | 03 derde verdieping | 3 | 23.35 | 7.005 | 21.015 | 70.05 | 70.05 | 21.015 | 01 | Woonfunctie | 40 | Noord
Gevelwand | 04 vierde verdieping | 3 | 24.1 | 7.23 | 21.69 | 72.3 | 72.3 | 21.69 | 01 | Woonfunctie | 40 | Oost
Gevelwand | 04 vierde verdieping | 3 | 23.35 | 7.005 | 21.015 | 70.05 | 70.05 | 21.015 | 02 | Woonfunctie | 40 | Zuid
Gevelwand | 04 vierde verdieping | 3 | 24.1 | 7.23 | 21.69 | 72.3 | 72.3 | 21.69 | 02 | Woonfunctie | 40 | West
Gevelwand | 04 vierde verdieping | 3 | 23.35 | 7.005 | 21.015 | 70.05 | 70.05 | 21.015 | 01 | Woonfunctie | 40 | Noord
Gevelwand | 05 vijfde verdieping | 3 | 24.1 | 7.23 | 21.69 | 72.3 | 72.3 | 21.69 | 01 | Woonfunctie | 40 | Oost
Gevelwand | 05 vijfde verdieping | 3 | 23.35 | 7.005 | 21.015 | 70.05 | 70.05 | 21.015 | 02 | Woonfunctie | 40 | Zuid
Gevelwand | 05 vijfde verdieping | 3 | 24.1 | 7.23 | 21.69 | 72.3 | 72.3 | 21.69 | 02 | Woonfunctie | 40 | West
Gevelwand | 05 vijfde verdieping | 3 | 23.35 | 7.005 | 21.015 | 70.05 | 70.05 | 21.015 | 01 | Woonfunctie | 40 | Noord
Gevelwand | 06 zesde verdieping | 3 | 24.1 | 7.23 | 21.69 | 72.3 | 72.3 | 21.69 | 01 | Woonfunctie | 40 | Oost
Gevelwand | 06 zesde verdieping | 3 | 23.35 | 7.005 | 21.015 | 70.05 | 70.05 | 21.015 | 02 | Woonfunctie | 40 | Zuid
Gevelwand | 06 zesde verdieping | 3 | 24.1 | 7.23 | 21.69 | 72.3 | 72.3 | 21.69 | 02 | Woonfunctie | 40 | West
Gevelwand | 06 zesde verdieping | 3 | 23.35 | 7.005 | 21.015 | 70.05 | 70.05 | 21.015 | 01 | Woonfunctie | 40 | Noord
Gevelwand | 07 zevende verdieping | 3 | 24.1 | 7.23 | 21.69 | 72.3 | 72.3 | 21.69 | 01 | Woonfunctie | 40 | Oost
Gevelwand | 07 zevende verdieping | 3 | 23.35 | 7.005 | 21.015 | 70.05 | 70.05 | 21.015 | 02 | Woonfunctie | 40 | Zuid
Gevelwand | 07 zevende verdieping | 3 | 24.1 | 7.23 | 21.69 | 72.3 | 72.3 | 21.69 | 02 | Woonfunctie | 40 | West
Gevelwand | 07 zevende verdieping | 3 | 23.35 | 7.005 | 21.015 | 70.05 | 70.05 | 21.015 | 01 | Woonfunctie | 40 | Noord
Gevelwand | 01 eerste verdieping | 3 | 7.05 | 2.115 | 6.345 | 21.15 | 21.15 | 6.345 | 02 | Bijeenkomstfunctie | 60 | Oost
Gevelwand | 01 eerste verdieping | 3 | 23.35 | 7.005 | 21.015 | 70.05 | 70.05 | 21.015 | 02 | Bijeenkomstfunctie | 60 | Zuid
Gevelwand | 01 eerste verdieping | 3 | 23.35 | 7.005 | 21.015 | 70.05 | 70.05 | 21.015 | 02 | Woonfunctie | 40 | Noord
Gevelwand | 08 achtste verdieping | 3 | 24.1 | 7.23 | 21.69 | 72.3 | 72.3 | 21.69 | 01 | Woonfunctie | 40 | Oost
Gevelwand | 08 achtste verdieping | 3 | 23.35 | 7.005 | 21.015 | 70.05 | 70.05 | 21.015 | 02 | Woonfunctie | 40 | Zuid
Gevelwand | 08 achtste verdieping | 3 | 24.1 | 7.23 | 21.69 | 72.3 | 72.3 | 21.69 | 02 | Woonfunctie | 40 | West
Gevelwand | 08 achtste verdieping | 3 | 23.35 | 7.005 | 21.015 | 70.05 | 70.05 | 21.015 | 01 | Woonfunctie | 40 | Noord
Gevelwand | 09 negende verdieping | 0.7 | 24.1 | 7.23 | 5.061 | 16.87 | 16.87 | 5.061 | 02 | Woonfunctie | 40 | Oost
Gevelwand | 09 negende verdieping | 0.7 | 23.35 | 7.005 | 4.9035 | 16.345 | 16.345 | 4.9035 | 02 | Woonfunctie | 40 | Zuid
Gevelwand | 09 negende verdieping | 0.7 | 24.1 | 7.23 | 5.061 | 16.87 | 16.87 | 5.061 | 02 | Woonfunctie | 40 | West
Gevelwand | 09 negende verdieping | 0.7 | 23.35 | 7.005 | 4.9035 | 16.345 | 16.345 | 4.9035 | 02 | Woonfunctie | 40 | Noord
Gevelwand | 01 eerste verdieping | 3 | 14.45 | 4.335 | 13.005 | 43.35 | 43.35 | 13.005 | 02 | Woonfunctie | 40 | Oost
Gevelwand | 01 eerste verdieping | 3 | 7.05 | 2.115 | 6.345 | 21.15 | 21.15 | 6.345 | 02 | Woonfunctie | 40 | Oost
Gevelwand | 01 eerste verdieping | 3 | 7.05 | 2.115 | 6.345 | 21.15 | 21.15 | 6.345 | 02 | Bijeenkomstfunctie | 60 | West
Gevelwand | 01 eerste verdieping | 3 | 14.45 | 4.335 | 13.005 | 43.35 | 43.35 | 13.005 | 02 | Woonfunctie | 40 | West
Gevelwand | 01 eerste verdieping | 3 | 7.05 | 2.115 | 6.345 | 21.15 | 21.15 | 6.345 | 02 | Woonfunctie | 40 | West
Gevelwand | 00 begane grond | 4.4 | 11.525 |  | 15.093 | 50.71 | 50.71 | 15.093 | 02 | Bijeenkomstfunctie | 60 | Oost
Gevelwand | 00 begane grond | 4.4 | 23.35 | 7.005 | 30.822 | 102.74 | 102.74 | 30.822 | 02 | Bijeenkomstfunctie | 60 | Zuid
Gevelwand | 00 begane grond | 3.9 | 6.775 | 2.0325 | 7.92675 | 26.4225 | 26.4225 | 7.92675 | 02 | Woonfunctie | 40 | West
Gevelwand | 00 begane grond | 4.4 | 23.35 | 7.005 | 30.822 | 102.74 | 95.3375 | 28.6013 | 02 | Woonfunctie | 40 | Noord
Gevelwand | 02 tweede verdieping | 0.7 | 4.325 | 1.2975 | 0.90825 | 3.0275 | 3.0275 | 0.90825 | 02 | Bijeenkomstfunctie | 0 | West
Gevelwand | 02 tweede verdieping | 0.7 | 23.35 | 7.005 | 4.9035 | 16.345 | 16.345 | 4.9035 | 02 | Bijeenkomstfunctie | 0 | Zuid
Gevelwand | 02 tweede verdieping | 0.7 | 4.325 | 1.2975 | 0.90825 | 3.0275 | 3.0275 | 0.90825 | 02 | Bijeenkomstfunctie | 0 | Oost
Gevelwand | 02 tweede verdieping | 0.7 | 4.325 | 1.2975 | 0.90825 | 3.0275 | 3.0275 | 0.90825 | 02 | Woonfunctie | 0 | West
Gevelwand | 02 tweede verdieping | 0.7 | 23.35 | 7.005 | 4.9035 | 16.345 | 16.345 | 4.9035 | 02 | Woonfunctie | 0 | Noord
Gevelwand | 02 tweede verdieping | 0.7 | 4.325 | 1.2975 | 0.90825 | 3.0275 | 3.0275 | 0.90825 | 02 | Woonfunctie | 0 | Oost
Gevelwand | 00 begane grond | 3.9 | 4.75 |  | 4.69725 | 16.0575 | 16.0575 | 4.69725 | 02 | Overige gebruiksfunctie | 10 | West
Gevelwand | 00 begane grond | 3.9 | 10.3 | 3.09 | 10.6657 | 35.5522 | 35.5522 | 10.6657 | 02 | Bijeenkomstfunctie | 80 | West
Gevelwand | 00 begane grond | 3.9 | 11.525 |  | 13.3643 | 44.9475 | 44.9475 | 13.3643 | 02 | Bijeenkomstfunctie | 60 | West
Gevelwand | 00 begane grond | 4.4 | 10.3 | 3.09 | 13.596 | 45.32 | 40.7023 | 12.2107 | 02 | Woonfunctie | 80 | Oost
Gevelwand | 00 begane grond | 4.4 | 4.75 |  | 5.40975 | 18.4325 | 18.4325 | 5.40975 | 02 | Overige gebruiksfunctie | 10 | Oost
Gevelwand | 00 begane grond | 4.4 | 6.775 | 2.0325 | 8.943 | 29.81 | 29.81 | 8.943 | 02 | Woonfunctie | 40 | Oost

# IfcWall: Basic Wall:22_WA_afbouw_binnenwand 100mm_gen (43)
Type - PredefinedType: STANDARD
Type - Pset_ReinforcementBarPitchOfWall - Description: Binnenwand
Type - Pset_WallCommon - LoadBearing: no
Classification: 22.10 binnenwanden; niet constructief, algemeen (verzamelniveau) (NL-SfB); Material: ntb_ntb_ntb
Qto_WallBaseQuantities - Width: 0.1 m
Pset_EnvironmentalImpactIndicators - Reference: 22_WA_afbouw_binnenwand 100mm_gen; sets with these values: 2
Pset_WallCommon - IsExternal: no; ExtendToStructure: no; Reference: 22_WA_afbouw_binnenwand 100mm_gen
Name | In | Height (m) | Length (m) | GrossFootprintArea (m2) | GrossVolume (m3) = NetVolume (m3) | GrossSideArea (m2) = NetSideArea (m2)
Binnenwand | 02 tweede verdieping | 2.75 | 1.45 | 0.145 | 0.152 | 1.52
Binnenwand | 02 tweede verdieping | 2.75 | 1.2 | 0.12 | 0.08325 | 0.8325
2 x Binnenwand | 02 tweede verdieping | 2.75 | 1.5 | 0.15 | 0.16575 | 1.6575
Binnenwand | 03 derde verdieping | 2.75 | 1.45 | 0.145 | 0.152 | 1.52
Binnenwand | 03 derde verdieping | 2.75 | 1.2 | 0.12 | 0.08325 | 0.8325
2 x Binnenwand | 03 derde verdieping | 2.75 | 1.5 | 0.15 | 0.16575 | 1.6575
Binnenwand | 04 vierde verdieping | 2.75 | 1.45 | 0.145 | 0.152 | 1.52
Binnenwand | 04 vierde verdieping | 2.75 | 1.2 | 0.12 | 0.08325 | 0.8325
2 x Binnenwand | 04 vierde verdieping | 2.75 | 1.5 | 0.15 | 0.16575 | 1.6575
Binnenwand | 05 vijfde verdieping | 2.75 | 1.45 | 0.145 | 0.152 | 1.52
Binnenwand | 05 vijfde verdieping | 2.75 | 1.2 | 0.12 | 0.08325 | 0.8325
2 x Binnenwand | 05 vijfde verdieping | 2.75 | 1.5 | 0.15 | 0.16575 | 1.6575
Binnenwand | 06 zesde verdieping | 2.75 | 1.45 | 0.145 | 0.152 | 1.52
Binnenwand | 06 zesde verdieping | 2.75 | 1.2 | 0.12 | 0.08325 | 0.8325
2 x Binnenwand | 06 zesde verdieping | 2.75 | 1.5 | 0.15 | 0.16575 | 1.6575
Binnenwand | 07 zevende verdieping | 2.75 | 1.45 | 0.145 | 0.152 | 1.52
Binnenwand | 07 zevende verdieping | 2.75 | 1.2 | 0.12 | 0.08325 | 0.8325
2 x Binnenwand | 07 zevende verdieping | 2.75 | 1.5 | 0.15 | 0.16575 | 1.6575
Binnenwand | 01 eerste verdieping | 2.75 | 1.45 | 0.145 | 0.152 | 1.52
Binnenwand | 01 eerste verdieping | 2.75 | 1.2 | 0.12 | 0.08325 | 0.8325
2 x Binnenwand | 01 eerste verdieping | 2.75 | 1.5 | 0.15 | 0.16575 | 1.6575
Binnenwand | 08 achtste verdieping | 2.75 | 1.45 | 0.145 | 0.152 | 1.52
Binnenwand | 08 achtste verdieping | 2.75 | 1.2 | 0.12 | 0.08325 | 0.8325
2 x Binnenwand | 08 achtste verdieping | 2.75 | 1.5 | 0.15 | 0.16575 | 1.6575
2 x Binnenwand | -1 kelder | 2.95 | 2.7 | 0.27 | 0.7965 | 7.965
2 x Binnenwand | -1 kelder | 2.95 | 3.265 | 0.3265 | 0.469675 | 4.69675
2 x Binnenwand | 00 begane grond | 3.65 | 1.2 | 0.12 | 0.19125 | 1.9125
Binnenwand | 00 begane grond | 3.65 | 7.25 | 0.725 | 2.188 | 21.88
2 x Binnenwand | 00 begane grond | 3.65 | 1.01 | 0.101 | 0.36865 | 3.6865
2 x Binnenwand | 00 begane grond | 3.65 | 4.45 | 0.445 | 1.3775 | 13.775

# IfcWall: Basic Wall:22_WA_afbouw_binnenwand 200mm_gen (2)
In: 08 achtste verdieping
Type - PredefinedType: STANDARD
Type - Pset_ReinforcementBarPitchOfWall - Description: Binnenwand
Type - Pset_WallCommon - LoadBearing: no
Classification: 22.10 binnenwanden; niet constructief, algemeen (verzamelniveau) (NL-SfB); Material: ntb_ntb_ntb
Qto_WallBaseQuantities - Height: 2.75 m; Length: 1.2 m; Width: 0.2 m; GrossFootprintArea: 0.24 m2; GrossVolume: 0.66 m3; GrossSideArea: 3.3 m2; NetSideArea: 3.3 m2; NetVolume: 0.66 m3
Pset_EnvironmentalImpactIndicators - Reference: 22_WA_afbouw_binnenwand 200mm_gen; sets with these values: 2
Pset_WallCommon - IsExternal: no; ExtendToStructure: no; Reference: 22_WA_afbouw_binnenwand 200mm_gen

# IfcWall: Basic Wall:22_WA_afbouw_binnenwand 250mm_gen (107)
Type - PredefinedType: STANDARD
Type - Pset_ReinforcementBarPitchOfWall - Description: Binnenwand
Type - Pset_WallCommon - LoadBearing: no
Classification: 22.10 binnenwanden; niet constructief, algemeen (verzamelniveau) (NL-SfB); Material: ntb_ntb_ntb
Qto_WallBaseQuantities - Width: 0.25 m
Pset_EnvironmentalImpactIndicators - Reference: 22_WA_afbouw_binnenwand 250mm_gen; sets with these values: 2
Pset_WallCommon - IsExternal: no; ExtendToStructure: no; Reference: 22_WA_afbouw_binnenwand 250mm_gen
Name | In | Height (m) | Length (m) | GrossFootprintArea (m2) | GrossVolume (m3) | GrossSideArea (m2) = NetSideArea (m2) | NetVolume (m3)
Binnenwand | 02 tweede verdieping | 2.75 | 2.8 | 0.7 | 1.925 | 7.7 | 1.925
Binnenwand | 02 tweede verdieping | 2.75 | 1.815 | 0.45375 | 0.630937 | 2.52375 | 0.630938
2 x Binnenwand | 02 tweede verdieping | 2.75 | 3.075 | 0.76875 | 1.49719 | 5.98875 | 1.49719
4 x Binnenwand | 02 tweede verdieping | 2.75 | 7.25 | 1.8125 | 4.98437 | 19.9375 | 4.98437
2 x Binnenwand | 02 tweede verdieping | 2.75 | 6.675 | 1.66875 | 4.58906 | 18.3562 | 4.58906
Binnenwand | 02 tweede verdieping | 2.75 | 1.815 | 0.45375 | 0.630938 | 2.52375 | 0.630938
Binnenwand | 02 tweede verdieping | 2.75 | 2.7 | 0.675 | 1.85625 | 7.425 | 1.85625
Binnenwand | 03 derde verdieping | 2.75 | 2.8 | 0.7 | 1.925 | 7.7 | 1.925
Binnenwand | 03 derde verdieping | 2.75 | 1.815 | 0.45375 | 0.630937 | 2.52375 | 0.630938
2 x Binnenwand | 03 derde verdieping | 2.75 | 3.075 | 0.76875 | 1.49719 | 5.98875 | 1.49719
4 x Binnenwand | 03 derde verdieping | 2.75 | 7.25 | 1.8125 | 4.98437 | 19.9375 | 4.98437
2 x Binnenwand | 03 derde verdieping | 2.75 | 6.675 | 1.66875 | 4.58906 | 18.3562 | 4.58906
Binnenwand | 03 derde verdieping | 2.75 | 1.815 | 0.45375 | 0.630938 | 2.52375 | 0.630938
Binnenwand | 03 derde verdieping | 2.75 | 2.7 | 0.675 | 1.85625 | 7.425 | 1.85625
Binnenwand | 04 vierde verdieping | 2.75 | 2.8 | 0.7 | 1.925 | 7.7 | 1.925
Binnenwand | 04 vierde verdieping | 2.75 | 1.815 | 0.45375 | 0.630937 | 2.52375 | 0.630938
2 x Binnenwand | 04 vierde verdieping | 2.75 | 3.075 | 0.76875 | 1.49719 | 5.98875 | 1.49719
4 x Binnenwand | 04 vierde verdieping | 2.75 | 7.25 | 1.8125 | 4.98437 | 19.9375 | 4.98437
2 x Binnenwand | 04 vierde verdieping | 2.75 | 6.675 | 1.66875 | 4.58906 | 18.3562 | 4.58906
Binnenwand | 04 vierde verdieping | 2.75 | 1.815 | 0.45375 | 0.630938 | 2.52375 | 0.630938
Binnenwand | 04 vierde verdieping | 2.75 | 2.7 | 0.675 | 1.85625 | 7.425 | 1.85625
Binnenwand | 05 vijfde verdieping | 2.75 | 2.8 | 0.7 | 1.925 | 7.7 | 1.925
Binnenwand | 05 vijfde verdieping | 2.75 | 1.815 | 0.45375 | 0.630937 | 2.52375 | 0.630938
2 x Binnenwand | 05 vijfde verdieping | 2.75 | 3.075 | 0.76875 | 1.49719 | 5.98875 | 1.49719
4 x Binnenwand | 05 vijfde verdieping | 2.75 | 7.25 | 1.8125 | 4.98437 | 19.9375 | 4.98437
2 x Binnenwand | 05 vijfde verdieping | 2.75 | 6.675 | 1.66875 | 4.58906 | 18.3562 | 4.58906
Binnenwand | 05 vijfde verdieping | 2.75 | 1.815 | 0.45375 | 0.630938 | 2.52375 | 0.630938
Binnenwand | 05 vijfde verdieping | 2.75 | 2.7 | 0.675 | 1.85625 | 7.425 | 1.85625
Binnenwand | 06 zesde verdieping | 2.75 | 2.8 | 0.7 | 1.925 | 7.7 | 1.925
Binnenwand | 06 zesde verdieping | 2.75 | 1.815 | 0.45375 | 0.630937 | 2.52375 | 0.630938
2 x Binnenwand | 06 zesde verdieping | 2.75 | 3.075 | 0.76875 | 1.49719 | 5.98875 | 1.49719
4 x Binnenwand | 06 zesde verdieping | 2.75 | 7.25 | 1.8125 | 4.98437 | 19.9375 | 4.98437
2 x Binnenwand | 06 zesde verdieping | 2.75 | 6.675 | 1.66875 | 4.58906 | 18.3562 | 4.58906
Binnenwand | 06 zesde verdieping | 2.75 | 1.815 | 0.45375 | 0.630938 | 2.52375 | 0.630938
Binnenwand | 06 zesde verdieping | 2.75 | 2.7 | 0.675 | 1.85625 | 7.425 | 1.85625
Binnenwand | 07 zevende verdieping | 2.75 | 2.8 | 0.7 | 1.925 | 7.7 | 1.925
2 x Binnenwand | 07 zevende verdieping | 2.75 | 1.815 | 0.45375 | 0.630937 | 2.52375 | 0.630938
2 x Binnenwand | 07 zevende verdieping | 2.75 | 3.075 | 0.76875 | 1.49719 | 5.98875 | 1.49719
4 x Binnenwand | 07 zevende verdieping | 2.75 | 7.25 | 1.8125 | 4.98437 | 19.9375 | 4.98437
2 x Binnenwand | 07 zevende verdieping | 2.75 | 6.675 | 1.66875 | 4.58906 | 18.3562 | 4.58906
Binnenwand | 07 zevende verdieping | 2.75 | 2.7 | 0.675 | 1.85625 | 7.425 | 1.85625
Binnenwand | 01 eerste verdieping | 2.75 | 2.8 | 0.7 | 1.925 | 7.7 | 1.925
Binnenwand | 01 eerste verdieping | 2.75 | 1.815 | 0.45375 | 0.630937 | 2.52375 | 0.630938
2 x Binnenwand | 01 eerste verdieping | 2.75 | 3.075 | 0.76875 | 1.49719 | 5.98875 | 1.49719
8 x Binnenwand | 01 eerste verdieping | 2.75 | 7.25 | 1.8125 | 4.98437 | 19.9375 | 4.98437
2 x Binnenwand | 01 eerste verdieping | 2.75 | 4.5 | 1.125 | 3.09375 | 12.375 | 3.09375
Binnenwand | 01 eerste verdieping | 2.75 | 1.815 | 0.45375 | 0.630938 | 2.52375 | 0.630938
Binnenwand | 01 eerste verdieping | 2.75 | 2.7 | 0.675 | 1.85625 | 7.425 | 1.85625
Binnenwand | 08 achtste verdieping | 2.75 | 2.8 | 0.7 | 1.925 | 7.7 | 1.925
2 x Binnenwand | 08 achtste verdieping | 2.75 | 1.815 | 0.45375 | 0.630937 | 2.52375 | 0.630938
2 x Binnenwand | 08 achtste verdieping | 2.75 | 3.075 | 0.76875 | 1.49719 | 5.98875 | 1.49719
4 x Binnenwand | 08 achtste verdieping | 2.75 | 7.25 | 1.8125 | 4.98437 | 19.9375 | 4.98437
2 x Binnenwand | 08 achtste verdieping | 2.75 | 6.675 | 1.66875 | 4.58906 | 18.3562 | 4.58906
Binnenwand | 08 achtste verdieping | 2.75 | 2.7 | 0.675 | 1.85625 | 7.425 | 1.85625
Binnenwand | 00 begane grond | 3.65 | 7.25 | 1.8125 | 5.99875 | 23.995 | 5.99875
5 x Binnenwand | 00 begane grond | 3.65 | 7.25 | 1.8125 | 6.61562 | 26.4625 | 6.61562
Binnenwand | 00 begane grond | 3.65 | 7.25 | 1.8125 | 5.47 | 21.88 | 5.47

# IfcWall: Basic Wall:28_WA_skelet_wand 200mm_gen (50)
Type - PredefinedType: STANDARD
Type - Pset_ReinforcementBarPitchOfWall - Description: Constructieve wand
Type - Pset_WallCommon - LoadBearing: yes
Classification: 28.20 hoofddraagconstructies; wanden en vloeren, algemeen (verzamelniveau) (NL-SfB); Material: beton_gewapend_prefab-element
Qto_WallBaseQuantities - Width: 0.2 m
Pset_EnvironmentalImpactIndicators - Reference: 28_WA_skelet_wand 200mm_gen; sets with these values: 2
Pset_WallCommon - IsExternal: no; LoadBearing: no; ExtendToStructure: no; Reference: 28_WA_skelet_wand 200mm_gen
Name | In | Height (m) | Length (m) | GrossFootprintArea (m2) | GrossVolume (m3) = NetVolume (m3) | GrossSideArea (m2) = NetSideArea (m2)
Constructieve wand | 02 tweede verdieping | 2.75 | 2.95 | 0.59 | 1.6225 | 8.1125
Constructieve wand | 02 tweede verdieping | 2.75 | 3.7 | 0.74 | 1.075 | 5.375
Constructieve wand | 02 tweede verdieping | 2.75 | 2.75 | 0.55 | 1.5125 | 7.5625
2 x Constructieve wand | 02 tweede verdieping | 2.75 | 3.52 | 0.704 | 1.936 | 9.68
Constructieve wand | 03 derde verdieping | 2.75 | 2.95 | 0.59 | 1.6225 | 8.1125
Constructieve wand | 03 derde verdieping | 2.75 | 3.7 | 0.74 | 1.075 | 5.375
Constructieve wand | 03 derde verdieping | 2.75 | 2.75 | 0.55 | 1.5125 | 7.5625
2 x Constructieve wand | 03 derde verdieping | 2.75 | 3.52 | 0.704 | 1.936 | 9.68
Constructieve wand | 04 vierde verdieping | 2.75 | 2.95 | 0.59 | 1.6225 | 8.1125
Constructieve wand | 04 vierde verdieping | 2.75 | 3.7 | 0.74 | 1.075 | 5.375
Constructieve wand | 04 vierde verdieping | 2.75 | 2.75 | 0.55 | 1.5125 | 7.5625
2 x Constructieve wand | 04 vierde verdieping | 2.75 | 3.52 | 0.704 | 1.936 | 9.68
Constructieve wand | 05 vijfde verdieping | 2.75 | 2.95 | 0.59 | 1.6225 | 8.1125
Constructieve wand | 05 vijfde verdieping | 2.75 | 3.7 | 0.74 | 1.075 | 5.375
Constructieve wand | 05 vijfde verdieping | 2.75 | 2.75 | 0.55 | 1.5125 | 7.5625
2 x Constructieve wand | 05 vijfde verdieping | 2.75 | 3.52 | 0.704 | 1.936 | 9.68
Constructieve wand | 06 zesde verdieping | 2.75 | 2.95 | 0.59 | 1.6225 | 8.1125
Constructieve wand | 06 zesde verdieping | 2.75 | 3.7 | 0.74 | 1.075 | 5.375
Constructieve wand | 06 zesde verdieping | 2.75 | 2.75 | 0.55 | 1.5125 | 7.5625
2 x Constructieve wand | 06 zesde verdieping | 2.75 | 3.52 | 0.704 | 1.936 | 9.68
Constructieve wand | 07 zevende verdieping | 2.75 | 2.95 | 0.59 | 1.6225 | 8.1125
Constructieve wand | 07 zevende verdieping | 2.75 | 3.7 | 0.74 | 1.075 | 5.375
Constructieve wand | 07 zevende verdieping | 2.75 | 2.75 | 0.55 | 1.5125 | 7.5625
2 x Constructieve wand | 07 zevende verdieping | 2.75 | 3.52 | 0.704 | 1.936 | 9.68
Constructieve wand | 01 eerste verdieping | 2.75 | 2.95 | 0.59 | 1.6225 | 8.1125
Constructieve wand | 01 eerste verdieping | 2.75 | 3.7 | 0.74 | 1.075 | 5.375
Constructieve wand | 01 eerste verdieping | 2.75 | 2.75 | 0.55 | 1.5125 | 7.5625
2 x Constructieve wand | 01 eerste verdieping | 2.75 | 3.52 | 0.704 | 1.936 | 9.68
Constructieve wand | 08 achtste verdieping | 2.75 | 2.95 | 0.59 | 1.6225 | 8.1125
Constructieve wand | 08 achtste verdieping | 2.75 | 3.7 | 0.74 | 1.075 | 5.375
Constructieve wand | 08 achtste verdieping | 2.75 | 2.75 | 0.55 | 1.5125 | 7.5625
2 x Constructieve wand | 08 achtste verdieping | 2.75 | 3.52 | 0.704 | 1.936 | 9.68
2 x Constructieve wand | -1 kelder | 2.95 | 2.75 | 0.55 | 1.6225 | 8.1125
Constructieve wand | -1 kelder | 2.95 | 10.05 | 2.01 | 3.9825 | 19.9125
2 x Constructieve wand | -1 kelder | 2.95 | 3.52 | 0.704 | 2.0768 | 10.384
Constructieve wand | 00 begane grond | 3.65 | 2.95 | 0.59 | 2.1535 | 10.7675
Constructieve wand | 00 begane grond | 3.65 | 3.7 | 0.74 | 2.701 | 13.505
Constructieve wand | 00 begane grond | 3.65 | 2.75 | 0.55 | 2.0075 | 10.0375
2 x Constructieve wand | 00 begane grond | 3.65 | 6.12 | 1.224 | 4.4676 | 22.338

# IfcWall: Basic Wall:28_WA_skelet_wand 250mm_gen (62)
Type - PredefinedType: STANDARD
Type - Pset_ReinforcementBarPitchOfWall - Description: Constructieve wand
Type - Pset_WallCommon - LoadBearing: yes
Classification: 28.20 hoofddraagconstructies; wanden en vloeren, algemeen (verzamelniveau) (NL-SfB); Material: beton_gewapend_ihw
Qto_WallBaseQuantities - Width: 0.25 m
Pset_EnvironmentalImpactIndicators - Reference: 28_WA_skelet_wand 250mm_gen; sets with these values: 2
Pset_WallCommon - IsExternal: no; Reference: 28_WA_skelet_wand 250mm_gen; LoadBearing: no; ExtendToStructure: no
Name | In | Height (m) | Length (m) | GrossFootprintArea (m2) | GrossVolume (m3) | GrossSideArea (m2) = NetSideArea (m2) | NetVolume (m3)
Constructieve wand | 02 tweede verdieping | 2.75 | 24.1 | 6.025 | 16.5688 | 66.275 | 16.5688
2 x Constructieve wand | 02 tweede verdieping | 2.75 | 24.1 | 6.025 | 14.4087 | 57.635 | 14.4088
Constructieve wand | 02 tweede verdieping | 2.75 | 24.1 | 6.025 | 16.5688 | 66.275 | 16.5687
2 x Constructieve wand | 02 tweede verdieping | 2.75 | 7.25 | 1.8125 | 3.6475 | 14.59 | 3.6475
Constructieve wand | 03 derde verdieping | 2.75 | 24.1 | 6.025 | 16.5688 | 66.275 | 16.5688
2 x Constructieve wand | 03 derde verdieping | 2.75 | 24.1 | 6.025 | 14.4087 | 57.635 | 14.4088
Constructieve wand | 03 derde verdieping | 2.75 | 24.1 | 6.025 | 16.5688 | 66.275 | 16.5687
2 x Constructieve wand | 03 derde verdieping | 2.75 | 7.25 | 1.8125 | 3.6475 | 14.59 | 3.6475
Constructieve wand | 04 vierde verdieping | 2.75 | 24.1 | 6.025 | 16.5688 | 66.275 | 16.5688
2 x Constructieve wand | 04 vierde verdieping | 2.75 | 24.1 | 6.025 | 14.4087 | 57.635 | 14.4088
Constructieve wand | 04 vierde verdieping | 2.75 | 24.1 | 6.025 | 16.5688 | 66.275 | 16.5687
2 x Constructieve wand | 04 vierde verdieping | 2.75 | 7.25 | 1.8125 | 3.6475 | 14.59 | 3.6475
Constructieve wand | 05 vijfde verdieping | 2.75 | 24.1 | 6.025 | 16.5688 | 66.275 | 16.5688
2 x Constructieve wand | 05 vijfde verdieping | 2.75 | 24.1 | 6.025 | 14.4087 | 57.635 | 14.4088
Constructieve wand | 05 vijfde verdieping | 2.75 | 24.1 | 6.025 | 16.5688 | 66.275 | 16.5687
2 x Constructieve wand | 05 vijfde verdieping | 2.75 | 7.25 | 1.8125 | 3.6475 | 14.59 | 3.6475
Constructieve wand | 06 zesde verdieping | 2.75 | 24.1 | 6.025 | 16.5688 | 66.275 | 16.5688
2 x Constructieve wand | 06 zesde verdieping | 2.75 | 24.1 | 6.025 | 14.4087 | 57.635 | 14.4088
Constructieve wand | 06 zesde verdieping | 2.75 | 24.1 | 6.025 | 16.5688 | 66.275 | 16.5687
2 x Constructieve wand | 06 zesde verdieping | 2.75 | 7.25 | 1.8125 | 3.6475 | 14.59 | 3.6475
Constructieve wand | 07 zevende verdieping | 2.75 | 24.1 | 6.025 | 16.5688 | 66.275 | 16.5688
2 x Constructieve wand | 07 zevende verdieping | 2.75 | 24.1 | 6.025 | 14.4087 | 57.635 | 14.4088
Constructieve wand | 07 zevende verdieping | 2.75 | 24.1 | 6.025 | 16.5688 | 66.275 | 16.5687
2 x Constructieve wand | 07 zevende verdieping | 2.75 | 7.25 | 1.8125 | 3.6475 | 14.59 | 3.6475
2 x Constructieve wand | 01 eerste verdieping | 2.75 | 33.35 | 8.3375 | 18.8481 | 75.3925 | 18.8481
4 x Constructieve wand | 01 eerste verdieping | 2.75 | 6.9 | 1.725 | 4.74375 | 18.975 | 4.74375
Constructieve wand | 01 eerste verdieping | 2.75 | 7.25 | 1.8125 | 4.98438 | 19.9375 | 4.98438
Constructieve wand | 01 eerste verdieping | 2.75 | 7.25 | 1.8125 | 4.98437 | 19.9375 | 4.98437
Constructieve wand | 08 achtste verdieping | 2.75 | 24.1 | 6.025 | 16.5688 | 66.275 | 16.5688
2 x Constructieve wand | 08 achtste verdieping | 2.75 | 24.1 | 6.025 | 14.4087 | 57.635 | 14.4088
Constructieve wand | 08 achtste verdieping | 2.75 | 24.1 | 6.025 | 16.5688 | 66.275 | 16.5687
2 x Constructieve wand | 08 achtste verdieping | 2.75 | 7.25 | 1.8125 | 3.6475 | 14.59 | 3.6475
Constructieve wand | -1 kelder | 2.95 | 10.05 | 2.5125 | 7.41187 | 29.6475 | 7.41188
Constructieve wand | -1 kelder | 2.95 | 10.3 | 2.575 | 7.59625 | 30.385 | 7.59625
Constructieve wand | -1 kelder | 2.95 | 7.5 | 1.875 | 4.91437 | 19.6575 | 4.91437
Constructieve wand | -1 kelder | 2.95 | 7.75 | 1.9375 | 5.09875 | 20.395 | 5.09875
2 x Constructieve wand | 01 eerste verdieping | 2.75 | 14.15 | 3.5375 | 9.72812 | 38.9125 | 9.72812
2 x Constructieve wand | 00 begane grond | 3.65 | 33.35 | 8.3375 | 28.6606 | 114.642 | 28.6606
Constructieve wand | 00 begane grond | 3.65 | 7.25 | 1.8125 | 6.61563 | 26.4625 | 6.61562
Constructieve wand | 00 begane grond | 3.65 | 33.35 | 8.3375 | 25.6806 | 102.722 | 25.6806
Constructieve wand | 00 begane grond | 3.65 | 7.25 | 1.8125 | 6.61562 | 26.4625 | 6.61562
Constructieve wand | 00 begane grond | 3.65 | 33.35 | 8.3375 | 24.4806 | 97.9225 | 24.4806
